VERSION 5.7 ;
BUSBITCHARS "[]" ;
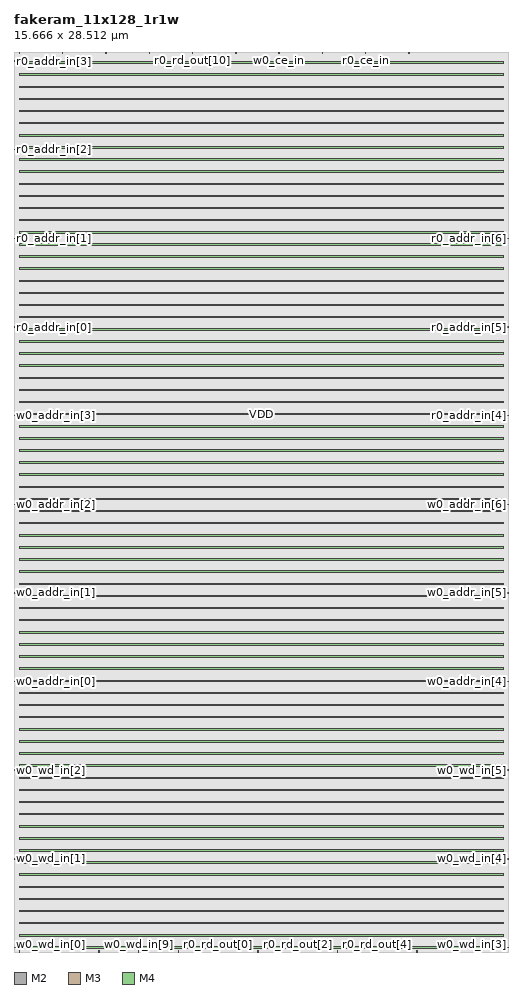
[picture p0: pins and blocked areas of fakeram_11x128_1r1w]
MACRO fakeram_11x128_1r1w
  FOREIGN fakeram_11x128_1r1w 0 0 ;
  SYMMETRY X Y R90 ;
  SIZE 15.666 BY 28.512 ;
  CLASS BLOCK ;
  PIN w0_wd_in[0]
    DIRECTION INPUT ;
    USE SIGNAL ;
    SHAPE ABUTMENT ;
    PORT
      LAYER M2 ;
      RECT 0.000 0.138 0.036 0.150 ;
    END
  END w0_wd_in[0]
  PIN w0_wd_in[1]
    DIRECTION INPUT ;
    USE SIGNAL ;
    SHAPE ABUTMENT ;
    PORT
      LAYER M2 ;
      RECT 0.000 2.946 0.036 2.958 ;
    END
  END w0_wd_in[1]
  PIN w0_wd_in[2]
    DIRECTION INPUT ;
    USE SIGNAL ;
    SHAPE ABUTMENT ;
    PORT
      LAYER M2 ;
      RECT 0.000 5.754 0.036 5.766 ;
    END
  END w0_wd_in[2]
  PIN w0_wd_in[3]
    DIRECTION INPUT ;
    USE SIGNAL ;
    SHAPE ABUTMENT ;
    PORT
      LAYER M2 ;
      RECT 15.630 0.138 15.666 0.150 ;
    END
  END w0_wd_in[3]
  PIN w0_wd_in[4]
    DIRECTION INPUT ;
    USE SIGNAL ;
    SHAPE ABUTMENT ;
    PORT
      LAYER M2 ;
      RECT 15.630 2.946 15.666 2.958 ;
    END
  END w0_wd_in[4]
  PIN w0_wd_in[5]
    DIRECTION INPUT ;
    USE SIGNAL ;
    SHAPE ABUTMENT ;
    PORT
      LAYER M2 ;
      RECT 15.630 5.754 15.666 5.766 ;
    END
  END w0_wd_in[5]
  PIN w0_wd_in[6]
    DIRECTION INPUT ;
    USE SIGNAL ;
    SHAPE ABUTMENT ;
    PORT
      LAYER M3 ;
      RECT 0.161 0.000 0.175 0.042 ;
    END
  END w0_wd_in[6]
  PIN w0_wd_in[7]
    DIRECTION INPUT ;
    USE SIGNAL ;
    SHAPE ABUTMENT ;
    PORT
      LAYER M3 ;
      RECT 1.421 0.000 1.435 0.042 ;
    END
  END w0_wd_in[7]
  PIN w0_wd_in[8]
    DIRECTION INPUT ;
    USE SIGNAL ;
    SHAPE ABUTMENT ;
    PORT
      LAYER M3 ;
      RECT 2.681 0.000 2.695 0.042 ;
    END
  END w0_wd_in[8]
  PIN w0_wd_in[9]
    DIRECTION INPUT ;
    USE SIGNAL ;
    SHAPE ABUTMENT ;
    PORT
      LAYER M3 ;
      RECT 3.941 0.000 3.955 0.042 ;
    END
  END w0_wd_in[9]
  PIN w0_wd_in[10]
    DIRECTION INPUT ;
    USE SIGNAL ;
    SHAPE ABUTMENT ;
    PORT
      LAYER M3 ;
      RECT 5.201 0.000 5.215 0.042 ;
    END
  END w0_wd_in[10]
  PIN r0_rd_out[0]
    DIRECTION OUTPUT ;
    USE SIGNAL ;
    SHAPE ABUTMENT ;
    PORT
      LAYER M3 ;
      RECT 6.461 0.000 6.475 0.042 ;
    END
  END r0_rd_out[0]
  PIN r0_rd_out[1]
    DIRECTION OUTPUT ;
    USE SIGNAL ;
    SHAPE ABUTMENT ;
    PORT
      LAYER M3 ;
      RECT 7.721 0.000 7.735 0.042 ;
    END
  END r0_rd_out[1]
  PIN r0_rd_out[2]
    DIRECTION OUTPUT ;
    USE SIGNAL ;
    SHAPE ABUTMENT ;
    PORT
      LAYER M3 ;
      RECT 8.981 0.000 8.995 0.042 ;
    END
  END r0_rd_out[2]
  PIN r0_rd_out[3]
    DIRECTION OUTPUT ;
    USE SIGNAL ;
    SHAPE ABUTMENT ;
    PORT
      LAYER M3 ;
      RECT 10.241 0.000 10.255 0.042 ;
    END
  END r0_rd_out[3]
  PIN r0_rd_out[4]
    DIRECTION OUTPUT ;
    USE SIGNAL ;
    SHAPE ABUTMENT ;
    PORT
      LAYER M3 ;
      RECT 11.501 0.000 11.515 0.042 ;
    END
  END r0_rd_out[4]
  PIN r0_rd_out[5]
    DIRECTION OUTPUT ;
    USE SIGNAL ;
    SHAPE ABUTMENT ;
    PORT
      LAYER M3 ;
      RECT 12.761 0.000 12.775 0.042 ;
    END
  END r0_rd_out[5]
  PIN r0_rd_out[6]
    DIRECTION OUTPUT ;
    USE SIGNAL ;
    SHAPE ABUTMENT ;
    PORT
      LAYER M3 ;
      RECT 0.161 28.470 0.175 28.512 ;
    END
  END r0_rd_out[6]
  PIN r0_rd_out[7]
    DIRECTION OUTPUT ;
    USE SIGNAL ;
    SHAPE ABUTMENT ;
    PORT
      LAYER M3 ;
      RECT 1.533 28.470 1.547 28.512 ;
    END
  END r0_rd_out[7]
  PIN r0_rd_out[8]
    DIRECTION OUTPUT ;
    USE SIGNAL ;
    SHAPE ABUTMENT ;
    PORT
      LAYER M3 ;
      RECT 2.905 28.470 2.919 28.512 ;
    END
  END r0_rd_out[8]
  PIN r0_rd_out[9]
    DIRECTION OUTPUT ;
    USE SIGNAL ;
    SHAPE ABUTMENT ;
    PORT
      LAYER M3 ;
      RECT 4.277 28.470 4.291 28.512 ;
    END
  END r0_rd_out[9]
  PIN r0_rd_out[10]
    DIRECTION OUTPUT ;
    USE SIGNAL ;
    SHAPE ABUTMENT ;
    PORT
      LAYER M3 ;
      RECT 5.649 28.470 5.663 28.512 ;
    END
  END r0_rd_out[10]
  PIN w0_addr_in[0]
    DIRECTION INPUT ;
    USE SIGNAL ;
    SHAPE ABUTMENT ;
    PORT
      LAYER M2 ;
      RECT 0.000 8.562 0.036 8.574 ;
    END
  END w0_addr_in[0]
  PIN w0_addr_in[1]
    DIRECTION INPUT ;
    USE SIGNAL ;
    SHAPE ABUTMENT ;
    PORT
      LAYER M2 ;
      RECT 0.000 11.370 0.036 11.382 ;
    END
  END w0_addr_in[1]
  PIN w0_addr_in[2]
    DIRECTION INPUT ;
    USE SIGNAL ;
    SHAPE ABUTMENT ;
    PORT
      LAYER M2 ;
      RECT 0.000 14.178 0.036 14.190 ;
    END
  END w0_addr_in[2]
  PIN w0_addr_in[3]
    DIRECTION INPUT ;
    USE SIGNAL ;
    SHAPE ABUTMENT ;
    PORT
      LAYER M2 ;
      RECT 0.000 16.986 0.036 16.998 ;
    END
  END w0_addr_in[3]
  PIN w0_addr_in[4]
    DIRECTION INPUT ;
    USE SIGNAL ;
    SHAPE ABUTMENT ;
    PORT
      LAYER M2 ;
      RECT 15.630 8.562 15.666 8.574 ;
    END
  END w0_addr_in[4]
  PIN w0_addr_in[5]
    DIRECTION INPUT ;
    USE SIGNAL ;
    SHAPE ABUTMENT ;
    PORT
      LAYER M2 ;
      RECT 15.630 11.370 15.666 11.382 ;
    END
  END w0_addr_in[5]
  PIN w0_addr_in[6]
    DIRECTION INPUT ;
    USE SIGNAL ;
    SHAPE ABUTMENT ;
    PORT
      LAYER M2 ;
      RECT 15.630 14.178 15.666 14.190 ;
    END
  END w0_addr_in[6]
  PIN r0_addr_in[0]
    DIRECTION INPUT ;
    USE SIGNAL ;
    SHAPE ABUTMENT ;
    PORT
      LAYER M2 ;
      RECT 0.000 19.794 0.036 19.806 ;
    END
  END r0_addr_in[0]
  PIN r0_addr_in[1]
    DIRECTION INPUT ;
    USE SIGNAL ;
    SHAPE ABUTMENT ;
    PORT
      LAYER M2 ;
      RECT 0.000 22.602 0.036 22.614 ;
    END
  END r0_addr_in[1]
  PIN r0_addr_in[2]
    DIRECTION INPUT ;
    USE SIGNAL ;
    SHAPE ABUTMENT ;
    PORT
      LAYER M2 ;
      RECT 0.000 25.410 0.036 25.422 ;
    END
  END r0_addr_in[2]
  PIN r0_addr_in[3]
    DIRECTION INPUT ;
    USE SIGNAL ;
    SHAPE ABUTMENT ;
    PORT
      LAYER M2 ;
      RECT 0.000 28.218 0.036 28.230 ;
    END
  END r0_addr_in[3]
  PIN r0_addr_in[4]
    DIRECTION INPUT ;
    USE SIGNAL ;
    SHAPE ABUTMENT ;
    PORT
      LAYER M2 ;
      RECT 15.630 16.986 15.666 16.998 ;
    END
  END r0_addr_in[4]
  PIN r0_addr_in[5]
    DIRECTION INPUT ;
    USE SIGNAL ;
    SHAPE ABUTMENT ;
    PORT
      LAYER M2 ;
      RECT 15.630 19.794 15.666 19.806 ;
    END
  END r0_addr_in[5]
  PIN r0_addr_in[6]
    DIRECTION INPUT ;
    USE SIGNAL ;
    SHAPE ABUTMENT ;
    PORT
      LAYER M2 ;
      RECT 15.630 22.602 15.666 22.614 ;
    END
  END r0_addr_in[6]
  PIN w0_we_in
    DIRECTION INPUT ;
    USE SIGNAL ;
    SHAPE ABUTMENT ;
    PORT
      LAYER M3 ;
      RECT 7.021 28.470 7.035 28.512 ;
    END
  END w0_we_in
  PIN w0_ce_in
    DIRECTION INPUT ;
    USE SIGNAL ;
    SHAPE ABUTMENT ;
    PORT
      LAYER M3 ;
      RECT 8.393 28.470 8.407 28.512 ;
    END
  END w0_ce_in
  PIN w0_clk
    DIRECTION INPUT ;
    USE SIGNAL ;
    SHAPE ABUTMENT ;
    PORT
      LAYER M3 ;
      RECT 9.765 28.470 9.779 28.512 ;
    END
  END w0_clk
  PIN r0_ce_in
    DIRECTION INPUT ;
    USE SIGNAL ;
    SHAPE ABUTMENT ;
    PORT
      LAYER M3 ;
      RECT 11.137 28.470 11.151 28.512 ;
    END
  END r0_ce_in
  PIN r0_clk
    DIRECTION INPUT ;
    USE SIGNAL ;
    SHAPE ABUTMENT ;
    PORT
      LAYER M3 ;
      RECT 12.509 28.470 12.523 28.512 ;
    END
  END r0_clk
  PIN VSS
    DIRECTION INOUT ;
    USE GROUND ;
    PORT
      LAYER M4 ;
      RECT 0.168 0.120 15.498 0.168 ;
      RECT 0.168 0.504 15.498 0.552 ;
      RECT 0.168 0.888 15.498 0.936 ;
      RECT 0.168 1.272 15.498 1.320 ;
      RECT 0.168 1.656 15.498 1.704 ;
      RECT 0.168 2.040 15.498 2.088 ;
      RECT 0.168 2.424 15.498 2.472 ;
      RECT 0.168 2.808 15.498 2.856 ;
      RECT 0.168 3.192 15.498 3.240 ;
      RECT 0.168 3.576 15.498 3.624 ;
      RECT 0.168 3.960 15.498 4.008 ;
      RECT 0.168 4.344 15.498 4.392 ;
      RECT 0.168 4.728 15.498 4.776 ;
      RECT 0.168 5.112 15.498 5.160 ;
      RECT 0.168 5.496 15.498 5.544 ;
      RECT 0.168 5.880 15.498 5.928 ;
      RECT 0.168 6.264 15.498 6.312 ;
      RECT 0.168 6.648 15.498 6.696 ;
      RECT 0.168 7.032 15.498 7.080 ;
      RECT 0.168 7.416 15.498 7.464 ;
      RECT 0.168 7.800 15.498 7.848 ;
      RECT 0.168 8.184 15.498 8.232 ;
      RECT 0.168 8.568 15.498 8.616 ;
      RECT 0.168 8.952 15.498 9.000 ;
      RECT 0.168 9.336 15.498 9.384 ;
      RECT 0.168 9.720 15.498 9.768 ;
      RECT 0.168 10.104 15.498 10.152 ;
      RECT 0.168 10.488 15.498 10.536 ;
      RECT 0.168 10.872 15.498 10.920 ;
      RECT 0.168 11.256 15.498 11.304 ;
      RECT 0.168 11.640 15.498 11.688 ;
      RECT 0.168 12.024 15.498 12.072 ;
      RECT 0.168 12.408 15.498 12.456 ;
      RECT 0.168 12.792 15.498 12.840 ;
      RECT 0.168 13.176 15.498 13.224 ;
      RECT 0.168 13.560 15.498 13.608 ;
      RECT 0.168 13.944 15.498 13.992 ;
      RECT 0.168 14.328 15.498 14.376 ;
      RECT 0.168 14.712 15.498 14.760 ;
      RECT 0.168 15.096 15.498 15.144 ;
      RECT 0.168 15.480 15.498 15.528 ;
      RECT 0.168 15.864 15.498 15.912 ;
      RECT 0.168 16.248 15.498 16.296 ;
      RECT 0.168 16.632 15.498 16.680 ;
      RECT 0.168 17.016 15.498 17.064 ;
      RECT 0.168 17.400 15.498 17.448 ;
      RECT 0.168 17.784 15.498 17.832 ;
      RECT 0.168 18.168 15.498 18.216 ;
      RECT 0.168 18.552 15.498 18.600 ;
      RECT 0.168 18.936 15.498 18.984 ;
      RECT 0.168 19.320 15.498 19.368 ;
      RECT 0.168 19.704 15.498 19.752 ;
      RECT 0.168 20.088 15.498 20.136 ;
      RECT 0.168 20.472 15.498 20.520 ;
      RECT 0.168 20.856 15.498 20.904 ;
      RECT 0.168 21.240 15.498 21.288 ;
      RECT 0.168 21.624 15.498 21.672 ;
      RECT 0.168 22.008 15.498 22.056 ;
      RECT 0.168 22.392 15.498 22.440 ;
      RECT 0.168 22.776 15.498 22.824 ;
      RECT 0.168 23.160 15.498 23.208 ;
      RECT 0.168 23.544 15.498 23.592 ;
      RECT 0.168 23.928 15.498 23.976 ;
      RECT 0.168 24.312 15.498 24.360 ;
      RECT 0.168 24.696 15.498 24.744 ;
      RECT 0.168 25.080 15.498 25.128 ;
      RECT 0.168 25.464 15.498 25.512 ;
      RECT 0.168 25.848 15.498 25.896 ;
      RECT 0.168 26.232 15.498 26.280 ;
      RECT 0.168 26.616 15.498 26.664 ;
      RECT 0.168 27.000 15.498 27.048 ;
      RECT 0.168 27.384 15.498 27.432 ;
      RECT 0.168 27.768 15.498 27.816 ;
      RECT 0.168 28.152 15.498 28.200 ;
    END
  END VSS
  PIN VDD
    DIRECTION INOUT ;
    USE POWER ;
    PORT
      LAYER M4 ;
      RECT 0.168 0.120 15.498 0.168 ;
      RECT 0.168 0.504 15.498 0.552 ;
      RECT 0.168 0.888 15.498 0.936 ;
      RECT 0.168 1.272 15.498 1.320 ;
      RECT 0.168 1.656 15.498 1.704 ;
      RECT 0.168 2.040 15.498 2.088 ;
      RECT 0.168 2.424 15.498 2.472 ;
      RECT 0.168 2.808 15.498 2.856 ;
      RECT 0.168 3.192 15.498 3.240 ;
      RECT 0.168 3.576 15.498 3.624 ;
      RECT 0.168 3.960 15.498 4.008 ;
      RECT 0.168 4.344 15.498 4.392 ;
      RECT 0.168 4.728 15.498 4.776 ;
      RECT 0.168 5.112 15.498 5.160 ;
      RECT 0.168 5.496 15.498 5.544 ;
      RECT 0.168 5.880 15.498 5.928 ;
      RECT 0.168 6.264 15.498 6.312 ;
      RECT 0.168 6.648 15.498 6.696 ;
      RECT 0.168 7.032 15.498 7.080 ;
      RECT 0.168 7.416 15.498 7.464 ;
      RECT 0.168 7.800 15.498 7.848 ;
      RECT 0.168 8.184 15.498 8.232 ;
      RECT 0.168 8.568 15.498 8.616 ;
      RECT 0.168 8.952 15.498 9.000 ;
      RECT 0.168 9.336 15.498 9.384 ;
      RECT 0.168 9.720 15.498 9.768 ;
      RECT 0.168 10.104 15.498 10.152 ;
      RECT 0.168 10.488 15.498 10.536 ;
      RECT 0.168 10.872 15.498 10.920 ;
      RECT 0.168 11.256 15.498 11.304 ;
      RECT 0.168 11.640 15.498 11.688 ;
      RECT 0.168 12.024 15.498 12.072 ;
      RECT 0.168 12.408 15.498 12.456 ;
      RECT 0.168 12.792 15.498 12.840 ;
      RECT 0.168 13.176 15.498 13.224 ;
      RECT 0.168 13.560 15.498 13.608 ;
      RECT 0.168 13.944 15.498 13.992 ;
      RECT 0.168 14.328 15.498 14.376 ;
      RECT 0.168 14.712 15.498 14.760 ;
      RECT 0.168 15.096 15.498 15.144 ;
      RECT 0.168 15.480 15.498 15.528 ;
      RECT 0.168 15.864 15.498 15.912 ;
      RECT 0.168 16.248 15.498 16.296 ;
      RECT 0.168 16.632 15.498 16.680 ;
      RECT 0.168 17.016 15.498 17.064 ;
      RECT 0.168 17.400 15.498 17.448 ;
      RECT 0.168 17.784 15.498 17.832 ;
      RECT 0.168 18.168 15.498 18.216 ;
      RECT 0.168 18.552 15.498 18.600 ;
      RECT 0.168 18.936 15.498 18.984 ;
      RECT 0.168 19.320 15.498 19.368 ;
      RECT 0.168 19.704 15.498 19.752 ;
      RECT 0.168 20.088 15.498 20.136 ;
      RECT 0.168 20.472 15.498 20.520 ;
      RECT 0.168 20.856 15.498 20.904 ;
      RECT 0.168 21.240 15.498 21.288 ;
      RECT 0.168 21.624 15.498 21.672 ;
      RECT 0.168 22.008 15.498 22.056 ;
      RECT 0.168 22.392 15.498 22.440 ;
      RECT 0.168 22.776 15.498 22.824 ;
      RECT 0.168 23.160 15.498 23.208 ;
      RECT 0.168 23.544 15.498 23.592 ;
      RECT 0.168 23.928 15.498 23.976 ;
      RECT 0.168 24.312 15.498 24.360 ;
      RECT 0.168 24.696 15.498 24.744 ;
      RECT 0.168 25.080 15.498 25.128 ;
      RECT 0.168 25.464 15.498 25.512 ;
      RECT 0.168 25.848 15.498 25.896 ;
      RECT 0.168 26.232 15.498 26.280 ;
      RECT 0.168 26.616 15.498 26.664 ;
      RECT 0.168 27.000 15.498 27.048 ;
      RECT 0.168 27.384 15.498 27.432 ;
      RECT 0.168 27.768 15.498 27.816 ;
      RECT 0.168 28.152 15.498 28.200 ;
    END
  END VDD
  OBS
    LAYER M1 ;
    RECT 0 0 15.666 28.512 ;
    LAYER M2 ;
    RECT 0 0 15.666 28.512 ;
    LAYER M3 ;
    RECT 0 0 15.666 28.512 ;
    LAYER M4 ;
    RECT 0 0 15.666 28.512 ;
  END
END fakeram_11x128_1r1w

END LIBRARY
